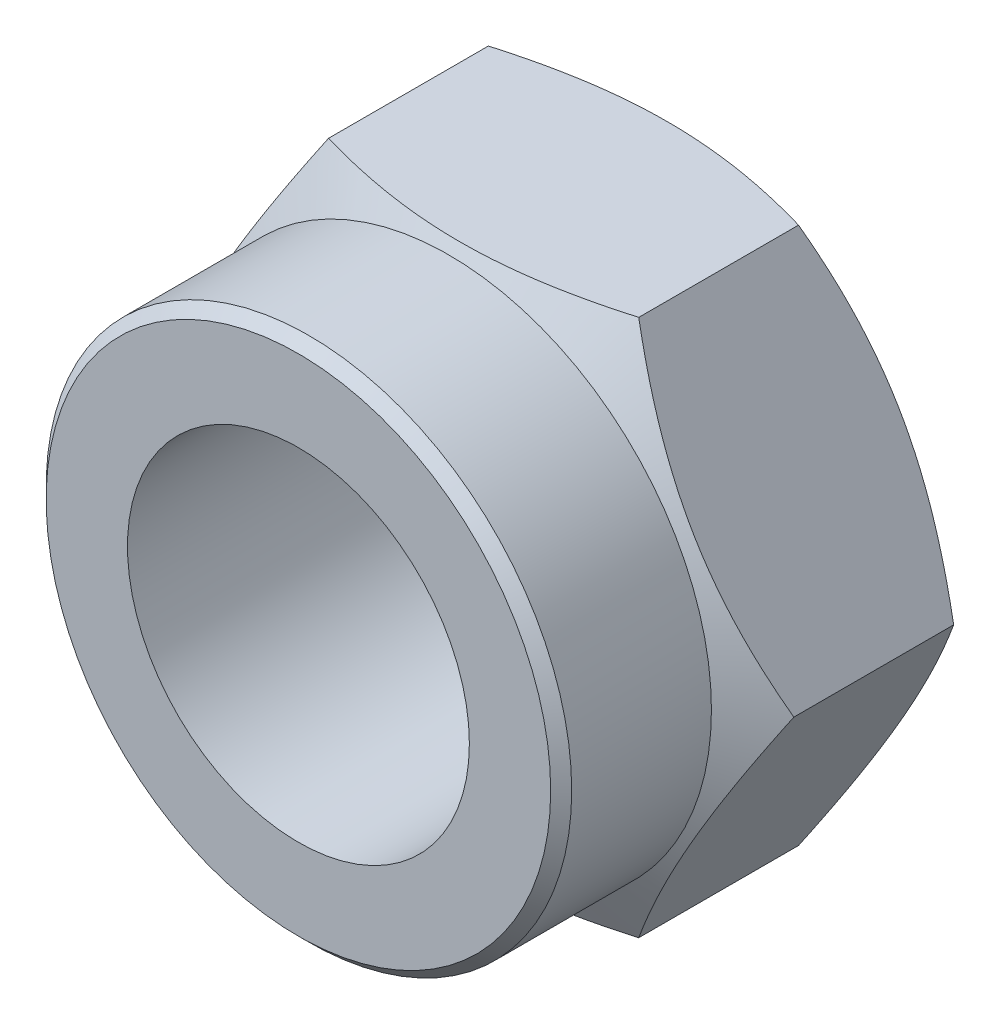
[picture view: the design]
ISO-10303-21;
HEADER;
FILE_DESCRIPTION(('STEP AP214'),'2;1');
FILE_NAME('part.step','',(''),(''),'','','');
FILE_SCHEMA(('AUTOMOTIVE_DESIGN { 1 0 10303 214 1 1 1 1 }'));
ENDSEC;
DATA;
#1=APPLICATION_CONTEXT('core data for automotive mechanical design processes');
#2=APPLICATION_PROTOCOL_DEFINITION('international standard','automotive_design',2000,#1);
#3=PRODUCT_CONTEXT('',#1,'mechanical');
#4=PRODUCT('Part','Part','',(#3));
#5=PRODUCT_RELATED_PRODUCT_CATEGORY('part','',(#4));
#6=PRODUCT_DEFINITION_FORMATION('','',#4);
#7=PRODUCT_DEFINITION_CONTEXT('part definition',#1,'design');
#8=PRODUCT_DEFINITION('design','',#6,#7);
#9=PRODUCT_DEFINITION_SHAPE('','',#8);
#10=(LENGTH_UNIT() NAMED_UNIT(*) SI_UNIT(.MILLI.,.METRE.));
#11=(NAMED_UNIT(*) PLANE_ANGLE_UNIT() SI_UNIT($,.RADIAN.));
#12=(NAMED_UNIT(*) SI_UNIT($,.STERADIAN.) SOLID_ANGLE_UNIT());
#13=UNCERTAINTY_MEASURE_WITH_UNIT(LENGTH_MEASURE(1.E-05),#10,'distance_accuracy_value','');
#14=(GEOMETRIC_REPRESENTATION_CONTEXT(3) GLOBAL_UNCERTAINTY_ASSIGNED_CONTEXT((#13)) GLOBAL_UNIT_ASSIGNED_CONTEXT((#10,
#11,#12)) REPRESENTATION_CONTEXT('',''));
#15=CARTESIAN_POINT('',(0.,0.,0.));
#16=DIRECTION('',(0.,0.,1.));
#17=DIRECTION('',(1.,0.,0.));
#18=AXIS2_PLACEMENT_3D('',#15,#16,#17);
#19=CARTESIAN_POINT('',(15.8771324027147,-27.5,-23.52));
#20=DIRECTION('',(0.,0.,1.));
#21=DIRECTION('',(1.,0.,0.));
#22=AXIS2_PLACEMENT_3D('',#19,#20,#21);
#23=PLANE('',#22);
#24=CARTESIAN_POINT('',(0.,0.,-23.52));
#25=DIRECTION('',(0.,0.,-1.));
#26=DIRECTION('',(-1.,0.,0.));
#27=AXIS2_PLACEMENT_3D('',#24,#25,#26);
#28=CIRCLE('',#27,25.555);
#29=CARTESIAN_POINT('',(-25.555,0.,-23.52));
#30=VERTEX_POINT('',#29);
#31=EDGE_CURVE('E268',#30,#30,#28,.T.);
#32=ORIENTED_EDGE('',*,*,#31,.T.);
#33=EDGE_LOOP('',(#32));
#34=FACE_BOUND('',#33,.T.);
#35=CARTESIAN_POINT('',(0.,0.,-23.52));
#36=DIRECTION('',(0.,0.,-1.));
#37=DIRECTION('',(-1.,0.,0.));
#38=AXIS2_PLACEMENT_3D('',#35,#36,#37);
#39=CIRCLE('',#38,19.45);
#40=CARTESIAN_POINT('',(-19.45,0.,-23.52));
#41=VERTEX_POINT('',#40);
#42=EDGE_CURVE('E281',#41,#41,#39,.T.);
#43=ORIENTED_EDGE('',*,*,#42,.F.);
#44=EDGE_LOOP('',(#43));
#45=FACE_BOUND('',#44,.T.);
#46=ADVANCED_FACE('F43',(#34,#45),#23,.F.);
#47=CARTESIAN_POINT('',(0.,0.,-23.52));
#48=DIRECTION('',(0.,0.,1.));
#49=DIRECTION('',(1.,0.,0.));
#50=AXIS2_PLACEMENT_3D('',#47,#48,#49);
#51=CYLINDRICAL_SURFACE('',#50,17.5);
#52=CARTESIAN_POINT('',(0.,0.,15.38));
#53=DIRECTION('',(0.,0.,1.));
#54=DIRECTION('',(1.,0.,0.));
#55=AXIS2_PLACEMENT_3D('',#52,#53,#54);
#56=CIRCLE('',#55,17.5);
#57=CARTESIAN_POINT('',(17.5,0.,15.38));
#58=VERTEX_POINT('',#57);
#59=EDGE_CURVE('E280',#58,#58,#56,.T.);
#60=ORIENTED_EDGE('',*,*,#59,.T.);
#61=EDGE_LOOP('',(#60));
#62=FACE_BOUND('',#61,.T.);
#63=CARTESIAN_POINT('',(0.,0.,-21.57));
#64=DIRECTION('',(0.,0.,-1.));
#65=DIRECTION('',(-1.,0.,0.));
#66=AXIS2_PLACEMENT_3D('',#63,#64,#65);
#67=CIRCLE('',#66,17.5);
#68=CARTESIAN_POINT('',(-17.5,0.,-21.57));
#69=VERTEX_POINT('',#68);
#70=EDGE_CURVE('E289',#69,#69,#67,.T.);
#71=ORIENTED_EDGE('',*,*,#70,.T.);
#72=EDGE_LOOP('',(#71));
#73=FACE_BOUND('',#72,.T.);
#74=ADVANCED_FACE('F146',(#62,#73),#51,.F.);
#75=CARTESIAN_POINT('',(-15.8771324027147,-27.5,-23.52));
#76=DIRECTION('',(0.,-1.,0.));
#77=DIRECTION('',(1.,0.,0.));
#78=AXIS2_PLACEMENT_3D('',#75,#76,#77);
#79=PLANE('',#78);
#80=DIRECTION('',(0.,0.,1.));
#81=VECTOR('',#80,1.);
#82=CARTESIAN_POINT('',(15.8771324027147,-27.5,-23.52));
#83=LINE('',#82,#81);
#84=CARTESIAN_POINT('',(15.8771324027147,-27.5,-19.9408527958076));
#85=VERTEX_POINT('',#84);
#86=CARTESIAN_POINT('',(15.8771324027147,-27.5,-3.57914720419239));
#87=VERTEX_POINT('',#86);
#88=EDGE_CURVE('E126',#85,#87,#83,.T.);
#89=ORIENTED_EDGE('',*,*,#88,.T.);
#90=CARTESIAN_POINT('',(-41.9529404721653,-27.5,-14.2072780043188));
#91=CARTESIAN_POINT('',(-41.3498619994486,-27.5,-13.9160849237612));
#92=CARTESIAN_POINT('',(-40.7460496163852,-27.5,-13.6264069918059));
#93=CARTESIAN_POINT('',(-39.5368030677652,-27.5,-13.0504395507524));
#94=CARTESIAN_POINT('',(-38.9313688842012,-27.5,-12.7641500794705));
#95=CARTESIAN_POINT('',(-37.7186338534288,-27.5,-12.1952752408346));
#96=CARTESIAN_POINT('',(-37.1113327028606,-27.5,-11.9126905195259));
#97=CARTESIAN_POINT('',(-35.8948027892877,-27.5,-11.351707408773));
#98=CARTESIAN_POINT('',(-35.2855740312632,-27.5,-11.0733090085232));
#99=CARTESIAN_POINT('',(-33.4476550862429,-27.5,-10.2418974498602));
#100=CARTESIAN_POINT('',(-32.2157452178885,-27.5,-9.69597054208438));
#101=CARTESIAN_POINT('',(-29.7417380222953,-27.5,-8.62775844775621));
#102=CARTESIAN_POINT('',(-28.4996412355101,-27.5,-8.1054720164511));
#103=CARTESIAN_POINT('',(-26.6200225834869,-27.5,-7.34162955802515));
#104=CARTESIAN_POINT('',(-25.9870438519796,-27.5,-7.08888221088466));
#105=CARTESIAN_POINT('',(-24.7176705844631,-27.5,-6.59212719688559));
#106=CARTESIAN_POINT('',(-24.0812761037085,-27.5,-6.34811938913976));
#107=CARTESIAN_POINT('',(-22.8046783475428,-27.5,-5.8699696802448));
#108=CARTESIAN_POINT('',(-22.1644745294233,-27.5,-5.63582922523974));
#109=CARTESIAN_POINT('',(-20.8800742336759,-27.5,-5.17879930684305));
#110=CARTESIAN_POINT('',(-20.2358778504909,-27.5,-4.95590957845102));
#111=CARTESIAN_POINT('',(-18.944590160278,-27.5,-4.52336181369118));
#112=CARTESIAN_POINT('',(-18.2975081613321,-27.5,-4.3136761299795));
#113=CARTESIAN_POINT('',(-16.9988609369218,-27.5,-3.90872451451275));
#114=CARTESIAN_POINT('',(-16.3472956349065,-27.5,-3.71345882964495));
#115=CARTESIAN_POINT('',(-14.3858917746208,-27.5,-3.1521805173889));
#116=CARTESIAN_POINT('',(-13.0688434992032,-27.5,-2.81051560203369));
#117=CARTESIAN_POINT('',(-11.0791469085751,-27.5,-2.35941057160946));
#118=CARTESIAN_POINT('',(-10.4133851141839,-27.5,-2.2192457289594));
#119=CARTESIAN_POINT('',(-9.07745639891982,-27.5,-1.96161324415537));
#120=CARTESIAN_POINT('',(-8.407289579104,-27.5,-1.84414508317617));
#121=CARTESIAN_POINT('',(-7.06301937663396,-27.5,-1.63399737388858));
#122=CARTESIAN_POINT('',(-6.38891574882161,-27.5,-1.54131938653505));
#123=CARTESIAN_POINT('',(-5.03755485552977,-27.5,-1.38261853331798));
#124=CARTESIAN_POINT('',(-4.3602975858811,-27.5,-1.31659570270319));
#125=CARTESIAN_POINT('',(-3.00782609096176,-27.5,-1.21297427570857));
#126=CARTESIAN_POINT('',(-2.33262527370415,-27.5,-1.1752018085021));
#127=CARTESIAN_POINT('',(-0.981233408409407,-27.5,-1.12827728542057));
#128=CARTESIAN_POINT('',(-0.305042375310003,-27.5,-1.11912480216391));
#129=CARTESIAN_POINT('',(1.04693403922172,-27.5,-1.12965648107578));
#130=CARTESIAN_POINT('',(1.72271948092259,-27.5,-1.14933283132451));
#131=CARTESIAN_POINT('',(3.07287323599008,-27.5,-1.2170378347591));
#132=CARTESIAN_POINT('',(3.7472414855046,-27.5,-1.26506773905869));
#133=CARTESIAN_POINT('',(5.38622566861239,-27.5,-1.41526016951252));
#134=CARTESIAN_POINT('',(6.34953811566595,-27.5,-1.53188000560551));
#135=CARTESIAN_POINT('',(8.26856130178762,-27.5,-1.81645090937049));
#136=CARTESIAN_POINT('',(9.22427087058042,-27.5,-1.98440972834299));
#137=CARTESIAN_POINT('',(11.12860836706,-27.5,-2.36594258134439));
#138=CARTESIAN_POINT('',(12.0772164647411,-27.5,-2.57961465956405));
#139=CARTESIAN_POINT('',(13.9646711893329,-27.5,-3.04594688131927));
#140=CARTESIAN_POINT('',(14.9035181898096,-27.5,-3.29860552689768));
#141=CARTESIAN_POINT('',(16.7933423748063,-27.5,-3.84312729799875));
#142=CARTESIAN_POINT('',(17.7440949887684,-27.5,-4.13576455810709));
#143=CARTESIAN_POINT('',(19.6362862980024,-27.5,-4.74984233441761));
#144=CARTESIAN_POINT('',(20.5777241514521,-27.5,-5.07128542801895));
#145=CARTESIAN_POINT('',(22.4467523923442,-27.5,-5.73620174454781));
#146=CARTESIAN_POINT('',(23.3743910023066,-27.5,-6.07953993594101));
#147=CARTESIAN_POINT('',(24.7600183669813,-27.5,-6.60924818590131));
#148=CARTESIAN_POINT('',(25.2208494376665,-27.5,-6.78823807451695));
#149=CARTESIAN_POINT('',(26.1407238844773,-27.5,-7.15071875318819));
#150=CARTESIAN_POINT('',(26.5997673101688,-27.5,-7.33420941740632));
#151=CARTESIAN_POINT('',(27.0579825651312,-27.5,-7.51974796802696));
#152=B_SPLINE_CURVE_WITH_KNOTS('',3,(#90,#91,#92,#93,#94,#95,#96,#97,#98,#99,#100,#101,#102,
#103,#104,#105,#106,#107,#108,#109,#110,#111,#112,#113,#114,#115,#116,#117,#118,#119,#120,#121,
#122,#123,#124,#125,#126,#127,#128,#129,#130,#131,#132,#133,#134,#135,#136,#137,#138,#139,#140,
#141,#142,#143,#144,#145,#146,#147,#148,#149,#150,#151),.UNSPECIFIED.,.F.,.F.,(4,2,2,2,2,2,2,2,
2,2,2,2,2,2,2,2,2,2,2,2,2,2,2,2,2,2,2,2,2,2,4),(0.,2.00909855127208,4.01821950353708,
6.02768627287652,8.03714785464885,12.0793239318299,16.121286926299,18.1659567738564,
20.2105936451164,22.2555291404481,24.3004164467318,26.3408689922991,28.3813564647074,
32.4607424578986,34.5015007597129,36.5422124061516,38.5830525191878,40.6238953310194,
42.6520717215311,44.6802178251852,46.7078144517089,48.7355005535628,51.6449146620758,
54.5547682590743,57.4709265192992,60.3869727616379,63.3707330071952,66.3547604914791,
69.3218933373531,70.8049872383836,72.2880397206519),.UNSPECIFIED.);
#153=CARTESIAN_POINT('',(-15.8771324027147,-27.5,-3.5791472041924));
#154=VERTEX_POINT('',#153);
#155=EDGE_CURVE('E59',#87,#154,#152,.F.);
#156=ORIENTED_EDGE('',*,*,#155,.T.);
#157=DIRECTION('',(0.,0.,1.));
#158=VECTOR('',#157,1.);
#159=CARTESIAN_POINT('',(-15.8771324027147,-27.5,-23.52));
#160=LINE('',#159,#158);
#161=CARTESIAN_POINT('',(-15.8771324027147,-27.5,-19.9408527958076));
#162=VERTEX_POINT('',#161);
#163=EDGE_CURVE('E115',#162,#154,#160,.T.);
#164=ORIENTED_EDGE('',*,*,#163,.F.);
#165=CARTESIAN_POINT('',(-41.9529404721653,-27.5,-9.31272199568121));
#166=CARTESIAN_POINT('',(-41.3498619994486,-27.5,-9.60391507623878));
#167=CARTESIAN_POINT('',(-40.7460496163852,-27.5,-9.89359300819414));
#168=CARTESIAN_POINT('',(-39.5368030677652,-27.5,-10.4695604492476));
#169=CARTESIAN_POINT('',(-38.9313688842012,-27.5,-10.7558499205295));
#170=CARTESIAN_POINT('',(-37.7186338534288,-27.5,-11.3247247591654));
#171=CARTESIAN_POINT('',(-37.1113327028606,-27.5,-11.607309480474));
#172=CARTESIAN_POINT('',(-35.8948027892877,-27.5,-12.168292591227));
#173=CARTESIAN_POINT('',(-35.2855740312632,-27.5,-12.4466909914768));
#174=CARTESIAN_POINT('',(-33.4476550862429,-27.5,-13.2781025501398));
#175=CARTESIAN_POINT('',(-32.2157452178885,-27.5,-13.8240294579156));
#176=CARTESIAN_POINT('',(-29.7417380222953,-27.5,-14.8922415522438));
#177=CARTESIAN_POINT('',(-28.4996412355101,-27.5,-15.4145279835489));
#178=CARTESIAN_POINT('',(-26.6200225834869,-27.5,-16.1783704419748));
#179=CARTESIAN_POINT('',(-25.9870438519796,-27.5,-16.4311177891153));
#180=CARTESIAN_POINT('',(-24.7176705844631,-27.5,-16.9278728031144));
#181=CARTESIAN_POINT('',(-24.0812761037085,-27.5,-17.1718806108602));
#182=CARTESIAN_POINT('',(-22.8046783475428,-27.5,-17.6500303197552));
#183=CARTESIAN_POINT('',(-22.1644745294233,-27.5,-17.8841707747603));
#184=CARTESIAN_POINT('',(-20.8800742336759,-27.5,-18.341200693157));
#185=CARTESIAN_POINT('',(-20.2358778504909,-27.5,-18.564090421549));
#186=CARTESIAN_POINT('',(-18.944590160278,-27.5,-18.9966381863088));
#187=CARTESIAN_POINT('',(-18.2975081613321,-27.5,-19.2063238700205));
#188=CARTESIAN_POINT('',(-16.9988609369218,-27.5,-19.6112754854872));
#189=CARTESIAN_POINT('',(-16.3472956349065,-27.5,-19.806541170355));
#190=CARTESIAN_POINT('',(-14.3858917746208,-27.5,-20.3678194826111));
#191=CARTESIAN_POINT('',(-13.0688434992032,-27.5,-20.7094843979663));
#192=CARTESIAN_POINT('',(-11.0791469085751,-27.5,-21.1605894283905));
#193=CARTESIAN_POINT('',(-10.4133851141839,-27.5,-21.3007542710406));
#194=CARTESIAN_POINT('',(-9.07745639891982,-27.5,-21.5583867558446));
#195=CARTESIAN_POINT('',(-8.407289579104,-27.5,-21.6758549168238));
#196=CARTESIAN_POINT('',(-7.06301937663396,-27.5,-21.8860026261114));
#197=CARTESIAN_POINT('',(-6.38891574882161,-27.5,-21.9786806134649));
#198=CARTESIAN_POINT('',(-5.03755485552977,-27.5,-22.137381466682));
#199=CARTESIAN_POINT('',(-4.3602975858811,-27.5,-22.2034042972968));
#200=CARTESIAN_POINT('',(-3.00782609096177,-27.5,-22.3070257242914));
#201=CARTESIAN_POINT('',(-2.33262527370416,-27.5,-22.3447981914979));
#202=CARTESIAN_POINT('',(-0.981233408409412,-27.5,-22.3917227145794));
#203=CARTESIAN_POINT('',(-0.305042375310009,-27.5,-22.4008751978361));
#204=CARTESIAN_POINT('',(1.04693403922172,-27.5,-22.3903435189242));
#205=CARTESIAN_POINT('',(1.72271948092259,-27.5,-22.3706671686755));
#206=CARTESIAN_POINT('',(3.07287323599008,-27.5,-22.3029621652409));
#207=CARTESIAN_POINT('',(3.7472414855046,-27.5,-22.2549322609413));
#208=CARTESIAN_POINT('',(5.38622566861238,-27.5,-22.1047398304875));
#209=CARTESIAN_POINT('',(6.34953811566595,-27.5,-21.9881199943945));
#210=CARTESIAN_POINT('',(8.26856130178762,-27.5,-21.7035490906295));
#211=CARTESIAN_POINT('',(9.22427087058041,-27.5,-21.535590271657));
#212=CARTESIAN_POINT('',(11.12860836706,-27.5,-21.1540574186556));
#213=CARTESIAN_POINT('',(12.0772164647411,-27.5,-20.9403853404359));
#214=CARTESIAN_POINT('',(13.9646711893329,-27.5,-20.4740531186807));
#215=CARTESIAN_POINT('',(14.9035181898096,-27.5,-20.2213944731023));
#216=CARTESIAN_POINT('',(16.7933423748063,-27.5,-19.6768727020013));
#217=CARTESIAN_POINT('',(17.7440949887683,-27.5,-19.3842354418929));
#218=CARTESIAN_POINT('',(19.6362862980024,-27.5,-18.7701576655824));
#219=CARTESIAN_POINT('',(20.577724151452,-27.5,-18.448714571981));
#220=CARTESIAN_POINT('',(22.4467523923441,-27.5,-17.7837982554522));
#221=CARTESIAN_POINT('',(23.3743910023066,-27.5,-17.440460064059));
#222=CARTESIAN_POINT('',(24.7600183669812,-27.5,-16.9107518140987));
#223=CARTESIAN_POINT('',(25.2208494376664,-27.5,-16.7317619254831));
#224=CARTESIAN_POINT('',(26.1407238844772,-27.5,-16.3692812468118));
#225=CARTESIAN_POINT('',(26.5997673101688,-27.5,-16.1857905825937));
#226=CARTESIAN_POINT('',(27.0579825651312,-27.5,-16.000252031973));
#227=B_SPLINE_CURVE_WITH_KNOTS('',3,(#165,#166,#167,#168,#169,#170,#171,#172,#173,#174,#175,
#176,#177,#178,#179,#180,#181,#182,#183,#184,#185,#186,#187,#188,#189,#190,#191,#192,#193,#194,
#195,#196,#197,#198,#199,#200,#201,#202,#203,#204,#205,#206,#207,#208,#209,#210,#211,#212,#213,
#214,#215,#216,#217,#218,#219,#220,#221,#222,#223,#224,#225,#226),.UNSPECIFIED.,.F.,.F.,(4,2,2,
2,2,2,2,2,2,2,2,2,2,2,2,2,2,2,2,2,2,2,2,2,2,2,2,2,2,2,4),(0.,2.00909855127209,4.01821950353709,
6.02768627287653,8.03714785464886,12.0793239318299,16.1212869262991,18.1659567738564,
20.2105936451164,22.2555291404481,24.3004164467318,26.3408689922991,28.3813564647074,
32.4607424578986,34.5015007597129,36.5422124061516,38.5830525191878,40.6238953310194,
42.6520717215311,44.6802178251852,46.7078144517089,48.7355005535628,51.6449146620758,
54.5547682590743,57.4709265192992,60.3869727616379,63.3707330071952,66.354760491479,
69.321893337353,70.8049872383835,72.2880397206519),.UNSPECIFIED.);
#228=EDGE_CURVE('E134',#162,#85,#227,.T.);
#229=ORIENTED_EDGE('',*,*,#228,.T.);
#230=EDGE_LOOP('',(#89,#156,#164,#229));
#231=FACE_BOUND('',#230,.T.);
#232=ADVANCED_FACE('F156',(#231),#79,.T.);
#233=CARTESIAN_POINT('',(-31.7542648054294,0.,-23.52));
#234=DIRECTION('',(-0.866025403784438,-0.5,0.));
#235=DIRECTION('',(0.5,-0.866025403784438,0.));
#236=AXIS2_PLACEMENT_3D('',#233,#234,#235);
#237=PLANE('',#236);
#238=ORIENTED_EDGE('',*,*,#163,.T.);
#239=CARTESIAN_POINT('',(-15.8770169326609,-27.5002,-3.57921387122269));
#240=CARTESIAN_POINT('',(-16.2259892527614,-26.8957622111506,-3.37774962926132));
#241=CARTESIAN_POINT('',(-16.5763227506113,-26.2889667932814,-3.18542761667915));
#242=CARTESIAN_POINT('',(-17.2797989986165,-25.0705101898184,-2.82160924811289));
#243=CARTESIAN_POINT('',(-17.6329426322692,-24.4588474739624,-2.65011974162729));
#244=CARTESIAN_POINT('',(-18.3427291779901,-23.229461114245,-2.33026818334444));
#245=CARTESIAN_POINT('',(-18.6993783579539,-22.6117266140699,-2.18196136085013));
#246=CARTESIAN_POINT('',(-19.4151397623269,-21.371991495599,-1.91167004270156));
#247=CARTESIAN_POINT('',(-19.7742517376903,-20.7499913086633,-1.78968292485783));
#248=CARTESIAN_POINT('',(-20.4857595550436,-19.5176236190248,-1.57720918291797));
#249=CARTESIAN_POINT('',(-20.8381026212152,-18.907347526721,-1.48601990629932));
#250=CARTESIAN_POINT('',(-21.5444032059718,-17.683999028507,-1.33311646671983));
#251=CARTESIAN_POINT('',(-21.8983607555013,-17.0709265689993,-1.27140287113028));
#252=CARTESIAN_POINT('',(-22.6068704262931,-15.8437518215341,-1.17900903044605));
#253=CARTESIAN_POINT('',(-22.9614213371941,-15.2296516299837,-1.14829190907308));
#254=CARTESIAN_POINT('',(-23.6708503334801,-14.0008845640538,-1.11855157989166));
#255=CARTESIAN_POINT('',(-24.025728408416,-13.3862177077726,-1.11952739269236));
#256=CARTESIAN_POINT('',(-24.6891773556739,-12.2370904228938,-1.15095918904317));
#257=CARTESIAN_POINT('',(-24.9977954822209,-11.7025481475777,-1.17758234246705));
#258=CARTESIAN_POINT('',(-25.6142949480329,-10.6347397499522,-1.25429236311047));
#259=CARTESIAN_POINT('',(-25.9221762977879,-10.1014736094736,-1.30437889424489));
#260=CARTESIAN_POINT('',(-26.5370884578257,-9.03641450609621,-1.42714762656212));
#261=CARTESIAN_POINT('',(-26.8441182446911,-8.50462331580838,-1.49985026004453));
#262=CARTESIAN_POINT('',(-27.4567077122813,-7.44358723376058,-1.66656449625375));
#263=CARTESIAN_POINT('',(-27.7622673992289,-6.9143423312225,-1.76057600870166));
#264=CARTESIAN_POINT('',(-28.6898814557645,-5.30766765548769,-2.07698651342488));
#265=CARTESIAN_POINT('',(-29.3093003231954,-4.23480270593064,-2.33095223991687));
#266=CARTESIAN_POINT('',(-30.2315881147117,-2.63735339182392,-2.76331683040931));
#267=CARTESIAN_POINT('',(-30.5376130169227,-2.10730271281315,-2.91585211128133));
#268=CARTESIAN_POINT('',(-31.1475461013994,-1.05086762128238,-3.23636496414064));
#269=CARTESIAN_POINT('',(-31.4514548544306,-0.524482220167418,-3.40433818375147));
#270=CARTESIAN_POINT('',(-31.7543802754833,0.000200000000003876,-3.5792138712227));
#271=B_SPLINE_CURVE_WITH_KNOTS('',3,(#239,#240,#241,#242,#243,#244,#245,#246,#247,#248,#249,
#250,#251,#252,#253,#254,#255,#256,#257,#258,#259,#260,#261,#262,#263,#264,#265,#266,#267,#268,
#269,#270),.UNSPECIFIED.,.F.,.F.,(4,2,2,2,2,2,2,2,2,2,2,2,2,2,2,4),(0.,2.17937596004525,
4.35946654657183,6.54467421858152,8.72966408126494,10.8607692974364,12.9919155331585,
15.120523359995,17.2490654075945,19.1020483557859,20.9550047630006,22.8096400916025,
24.6642675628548,28.4552152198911,30.3473870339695,32.2390270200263),.UNSPECIFIED.);
#272=CARTESIAN_POINT('',(-31.7542648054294,0.,-3.5791472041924));
#273=VERTEX_POINT('',#272);
#274=EDGE_CURVE('E97',#154,#273,#271,.T.);
#275=ORIENTED_EDGE('',*,*,#274,.T.);
#276=DIRECTION('',(0.,0.,1.));
#277=VECTOR('',#276,1.);
#278=CARTESIAN_POINT('',(-31.7542648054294,0.,-23.52));
#279=LINE('',#278,#277);
#280=CARTESIAN_POINT('',(-31.7542648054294,0.,-19.9408527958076));
#281=VERTEX_POINT('',#280);
#282=EDGE_CURVE('E109',#281,#273,#279,.T.);
#283=ORIENTED_EDGE('',*,*,#282,.F.);
#284=CARTESIAN_POINT('',(-31.7543802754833,0.00020000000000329,-19.9407861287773));
#285=CARTESIAN_POINT('',(-31.4054079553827,-0.604237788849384,-20.1422503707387));
#286=CARTESIAN_POINT('',(-31.0550744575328,-1.21103320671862,-20.3345723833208));
#287=CARTESIAN_POINT('',(-30.3515982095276,-2.42948981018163,-20.6983907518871));
#288=CARTESIAN_POINT('',(-29.9984545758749,-3.04115252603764,-20.8698802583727));
#289=CARTESIAN_POINT('',(-29.288668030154,-4.27053888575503,-21.1897318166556));
#290=CARTESIAN_POINT('',(-28.9320188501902,-4.88827338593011,-21.3380386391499));
#291=CARTESIAN_POINT('',(-28.2162574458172,-6.128008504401,-21.6083299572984));
#292=CARTESIAN_POINT('',(-27.8571454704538,-6.75000869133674,-21.7303170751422));
#293=CARTESIAN_POINT('',(-27.1456376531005,-7.98237638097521,-21.942790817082));
#294=CARTESIAN_POINT('',(-26.7932945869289,-8.59265247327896,-22.0339800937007));
#295=CARTESIAN_POINT('',(-26.0869940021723,-9.81600097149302,-22.1868835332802));
#296=CARTESIAN_POINT('',(-25.7330364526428,-10.4290734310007,-22.2485971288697));
#297=CARTESIAN_POINT('',(-25.024526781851,-11.6562481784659,-22.340990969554));
#298=CARTESIAN_POINT('',(-24.66997587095,-12.2703483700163,-22.3717080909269));
#299=CARTESIAN_POINT('',(-23.960546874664,-13.4991154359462,-22.4014484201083));
#300=CARTESIAN_POINT('',(-23.6056687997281,-14.1137822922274,-22.4004726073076));
#301=CARTESIAN_POINT('',(-22.9422198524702,-15.2629095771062,-22.3690408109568));
#302=CARTESIAN_POINT('',(-22.6336017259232,-15.7974518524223,-22.342417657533));
#303=CARTESIAN_POINT('',(-22.0171022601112,-16.8652602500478,-22.2657076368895));
#304=CARTESIAN_POINT('',(-21.7092209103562,-17.3985263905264,-22.2156211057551));
#305=CARTESIAN_POINT('',(-21.0943087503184,-18.4635854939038,-22.0928523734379));
#306=CARTESIAN_POINT('',(-20.787278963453,-18.9953766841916,-22.0201497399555));
#307=CARTESIAN_POINT('',(-20.1746894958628,-20.0564127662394,-21.8534355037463));
#308=CARTESIAN_POINT('',(-19.8691298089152,-20.5856576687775,-21.7594239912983));
#309=CARTESIAN_POINT('',(-18.9415157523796,-22.1923323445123,-21.4430134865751));
#310=CARTESIAN_POINT('',(-18.3220968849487,-23.2651972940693,-21.1890477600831));
#311=CARTESIAN_POINT('',(-17.3998090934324,-24.8626466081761,-20.7566831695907));
#312=CARTESIAN_POINT('',(-17.0937841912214,-25.3926972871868,-20.6041478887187));
#313=CARTESIAN_POINT('',(-16.4838511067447,-26.4491323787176,-20.2836350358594));
#314=CARTESIAN_POINT('',(-16.1799423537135,-26.9755177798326,-20.1156618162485));
#315=CARTESIAN_POINT('',(-15.8770169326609,-27.5002,-19.9407861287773));
#316=B_SPLINE_CURVE_WITH_KNOTS('',3,(#284,#285,#286,#287,#288,#289,#290,#291,#292,#293,#294,
#295,#296,#297,#298,#299,#300,#301,#302,#303,#304,#305,#306,#307,#308,#309,#310,#311,#312,#313,
#314,#315),.UNSPECIFIED.,.F.,.F.,(4,2,2,2,2,2,2,2,2,2,2,2,2,2,2,4),(0.,2.17937596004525,
4.35946654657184,6.54467421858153,8.72966408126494,10.8607692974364,12.9919155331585,
15.120523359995,17.2490654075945,19.1020483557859,20.9550047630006,22.8096400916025,
24.6642675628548,28.4552152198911,30.3473870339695,32.2390270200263),.UNSPECIFIED.);
#317=EDGE_CURVE('E171',#281,#162,#316,.T.);
#318=ORIENTED_EDGE('',*,*,#317,.T.);
#319=EDGE_LOOP('',(#238,#275,#283,#318));
#320=FACE_BOUND('',#319,.T.);
#321=ADVANCED_FACE('F108',(#320),#237,.T.);
#322=CARTESIAN_POINT('',(-15.8771324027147,27.5,-23.52));
#323=DIRECTION('',(-0.866025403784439,0.5,0.));
#324=DIRECTION('',(-0.5,-0.866025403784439,0.));
#325=AXIS2_PLACEMENT_3D('',#322,#323,#324);
#326=PLANE('',#325);
#327=ORIENTED_EDGE('',*,*,#282,.T.);
#328=CARTESIAN_POINT('',(-31.7543802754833,-0.000199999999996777,-3.5792138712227));
#329=CARTESIAN_POINT('',(-31.4054079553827,0.60423778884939,-3.37774962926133));
#330=CARTESIAN_POINT('',(-31.0550744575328,1.21103320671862,-3.18542761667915));
#331=CARTESIAN_POINT('',(-30.3515982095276,2.42948981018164,-2.8216092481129));
#332=CARTESIAN_POINT('',(-29.9984545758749,3.04115252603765,-2.6501197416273));
#333=CARTESIAN_POINT('',(-29.288668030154,4.27053888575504,-2.33026818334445));
#334=CARTESIAN_POINT('',(-28.9320188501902,4.88827338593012,-2.18196136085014));
#335=CARTESIAN_POINT('',(-28.2162574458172,6.12800850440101,-1.91167004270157));
#336=CARTESIAN_POINT('',(-27.8571454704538,6.75000869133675,-1.78968292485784));
#337=CARTESIAN_POINT('',(-27.1456376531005,7.98237638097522,-1.57720918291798));
#338=CARTESIAN_POINT('',(-26.7932945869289,8.59265247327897,-1.48601990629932));
#339=CARTESIAN_POINT('',(-26.0869940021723,9.81600097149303,-1.33311646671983));
#340=CARTESIAN_POINT('',(-25.7330364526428,10.4290734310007,-1.27140287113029));
#341=CARTESIAN_POINT('',(-25.024526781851,11.6562481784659,-1.17900903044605));
#342=CARTESIAN_POINT('',(-24.66997587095,12.2703483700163,-1.14829190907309));
#343=CARTESIAN_POINT('',(-23.960546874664,13.4991154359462,-1.11855157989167));
#344=CARTESIAN_POINT('',(-23.6056687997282,14.1137822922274,-1.11952739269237));
#345=CARTESIAN_POINT('',(-22.9422198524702,15.2629095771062,-1.15095918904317));
#346=CARTESIAN_POINT('',(-22.6336017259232,15.7974518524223,-1.17758234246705));
#347=CARTESIAN_POINT('',(-22.0171022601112,16.8652602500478,-1.25429236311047));
#348=CARTESIAN_POINT('',(-21.7092209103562,17.3985263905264,-1.3043788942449));
#349=CARTESIAN_POINT('',(-21.0943087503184,18.4635854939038,-1.42714762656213));
#350=CARTESIAN_POINT('',(-20.787278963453,18.9953766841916,-1.49985026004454));
#351=CARTESIAN_POINT('',(-20.1746894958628,20.0564127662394,-1.66656449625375));
#352=CARTESIAN_POINT('',(-19.8691298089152,20.5856576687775,-1.76057600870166));
#353=CARTESIAN_POINT('',(-18.9415157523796,22.1923323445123,-2.07698651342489));
#354=CARTESIAN_POINT('',(-18.3220968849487,23.2651972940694,-2.33095223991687));
#355=CARTESIAN_POINT('',(-17.3998090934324,24.8626466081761,-2.76331683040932));
#356=CARTESIAN_POINT('',(-17.0937841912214,25.3926972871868,-2.91585211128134));
#357=CARTESIAN_POINT('',(-16.4838511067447,26.4491323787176,-3.23636496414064));
#358=CARTESIAN_POINT('',(-16.1799423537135,26.9755177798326,-3.40433818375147));
#359=CARTESIAN_POINT('',(-15.8770169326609,27.5002,-3.5792138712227));
#360=B_SPLINE_CURVE_WITH_KNOTS('',3,(#328,#329,#330,#331,#332,#333,#334,#335,#336,#337,#338,
#339,#340,#341,#342,#343,#344,#345,#346,#347,#348,#349,#350,#351,#352,#353,#354,#355,#356,#357,
#358,#359),.UNSPECIFIED.,.F.,.F.,(4,2,2,2,2,2,2,2,2,2,2,2,2,2,2,4),(0.,2.17937596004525,
4.35946654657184,6.54467421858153,8.72966408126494,10.8607692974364,12.9919155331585,
15.120523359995,17.2490654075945,19.1020483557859,20.9550047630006,22.8096400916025,
24.6642675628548,28.4552152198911,30.3473870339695,32.2390270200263),.UNSPECIFIED.);
#361=CARTESIAN_POINT('',(-15.8771324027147,27.5,-3.5791472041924));
#362=VERTEX_POINT('',#361);
#363=EDGE_CURVE('E93',#273,#362,#360,.T.);
#364=ORIENTED_EDGE('',*,*,#363,.T.);
#365=DIRECTION('',(0.,0.,1.));
#366=VECTOR('',#365,1.);
#367=CARTESIAN_POINT('',(-15.8771324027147,27.5,-23.52));
#368=LINE('',#367,#366);
#369=CARTESIAN_POINT('',(-15.8771324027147,27.5,-19.9408527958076));
#370=VERTEX_POINT('',#369);
#371=EDGE_CURVE('E120',#370,#362,#368,.T.);
#372=ORIENTED_EDGE('',*,*,#371,.F.);
#373=CARTESIAN_POINT('',(-15.8770169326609,27.5002,-19.9407861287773));
#374=CARTESIAN_POINT('',(-16.2259892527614,26.8957622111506,-20.1422503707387));
#375=CARTESIAN_POINT('',(-16.5763227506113,26.2889667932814,-20.3345723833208));
#376=CARTESIAN_POINT('',(-17.2797989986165,25.0705101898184,-20.6983907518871));
#377=CARTESIAN_POINT('',(-17.6329426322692,24.4588474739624,-20.8698802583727));
#378=CARTESIAN_POINT('',(-18.3427291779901,23.229461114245,-21.1897318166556));
#379=CARTESIAN_POINT('',(-18.6993783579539,22.6117266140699,-21.3380386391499));
#380=CARTESIAN_POINT('',(-19.4151397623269,21.371991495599,-21.6083299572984));
#381=CARTESIAN_POINT('',(-19.7742517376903,20.7499913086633,-21.7303170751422));
#382=CARTESIAN_POINT('',(-20.4857595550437,19.5176236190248,-21.942790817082));
#383=CARTESIAN_POINT('',(-20.8381026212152,18.907347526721,-22.0339800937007));
#384=CARTESIAN_POINT('',(-21.5444032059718,17.683999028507,-22.1868835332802));
#385=CARTESIAN_POINT('',(-21.8983607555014,17.0709265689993,-22.2485971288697));
#386=CARTESIAN_POINT('',(-22.6068704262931,15.8437518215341,-22.3409909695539));
#387=CARTESIAN_POINT('',(-22.9614213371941,15.2296516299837,-22.3717080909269));
#388=CARTESIAN_POINT('',(-23.6708503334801,14.0008845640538,-22.4014484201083));
#389=CARTESIAN_POINT('',(-24.025728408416,13.3862177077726,-22.4004726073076));
#390=CARTESIAN_POINT('',(-24.6891773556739,12.2370904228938,-22.3690408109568));
#391=CARTESIAN_POINT('',(-24.9977954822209,11.7025481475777,-22.3424176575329));
#392=CARTESIAN_POINT('',(-25.6142949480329,10.6347397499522,-22.2657076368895));
#393=CARTESIAN_POINT('',(-25.9221762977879,10.1014736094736,-22.2156211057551));
#394=CARTESIAN_POINT('',(-26.5370884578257,9.03641450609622,-22.0928523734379));
#395=CARTESIAN_POINT('',(-26.8441182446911,8.50462331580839,-22.0201497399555));
#396=CARTESIAN_POINT('',(-27.4567077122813,7.44358723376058,-21.8534355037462));
#397=CARTESIAN_POINT('',(-27.7622673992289,6.9143423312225,-21.7594239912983));
#398=CARTESIAN_POINT('',(-28.6898814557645,5.3076676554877,-21.4430134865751));
#399=CARTESIAN_POINT('',(-29.3093003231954,4.23480270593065,-21.1890477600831));
#400=CARTESIAN_POINT('',(-30.2315881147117,2.63735339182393,-20.7566831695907));
#401=CARTESIAN_POINT('',(-30.5376130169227,2.10730271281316,-20.6041478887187));
#402=CARTESIAN_POINT('',(-31.1475461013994,1.05086762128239,-20.2836350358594));
#403=CARTESIAN_POINT('',(-31.4514548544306,0.524482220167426,-20.1156618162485));
#404=CARTESIAN_POINT('',(-31.7543802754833,-0.000199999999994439,-19.9407861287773));
#405=B_SPLINE_CURVE_WITH_KNOTS('',3,(#373,#374,#375,#376,#377,#378,#379,#380,#381,#382,#383,
#384,#385,#386,#387,#388,#389,#390,#391,#392,#393,#394,#395,#396,#397,#398,#399,#400,#401,#402,
#403,#404),.UNSPECIFIED.,.F.,.F.,(4,2,2,2,2,2,2,2,2,2,2,2,2,2,2,4),(0.,2.17937596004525,
4.35946654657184,6.54467421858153,8.72966408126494,10.8607692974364,12.9919155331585,
15.120523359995,17.2490654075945,19.1020483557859,20.9550047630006,22.8096400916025,
24.6642675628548,28.4552152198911,30.3473870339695,32.2390270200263),.UNSPECIFIED.);
#406=EDGE_CURVE('E116',#370,#281,#405,.T.);
#407=ORIENTED_EDGE('',*,*,#406,.T.);
#408=EDGE_LOOP('',(#327,#364,#372,#407));
#409=FACE_BOUND('',#408,.T.);
#410=ADVANCED_FACE('F114',(#409),#326,.T.);
#411=CARTESIAN_POINT('',(15.8771324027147,27.5,-23.52));
#412=DIRECTION('',(0.,1.,0.));
#413=DIRECTION('',(0.,0.,1.));
#414=AXIS2_PLACEMENT_3D('',#411,#412,#413);
#415=PLANE('',#414);
#416=ORIENTED_EDGE('',*,*,#371,.T.);
#417=CARTESIAN_POINT('',(-41.9529404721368,27.5,-14.207278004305));
#418=CARTESIAN_POINT('',(-41.3498619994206,27.5,-13.9160849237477));
#419=CARTESIAN_POINT('',(-40.7460496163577,27.5,-13.6264069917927));
#420=CARTESIAN_POINT('',(-39.5368030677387,27.5,-13.0504395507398));
#421=CARTESIAN_POINT('',(-38.9313688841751,27.5,-12.7641500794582));
#422=CARTESIAN_POINT('',(-37.7186338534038,27.5,-12.1952752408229));
#423=CARTESIAN_POINT('',(-37.111332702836,27.5,-11.9126905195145));
#424=CARTESIAN_POINT('',(-35.8948027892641,27.5,-11.3517074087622));
#425=CARTESIAN_POINT('',(-35.2855740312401,27.5,-11.0733090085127));
#426=CARTESIAN_POINT('',(-33.4476550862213,27.5,-10.2418974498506));
#427=CARTESIAN_POINT('',(-32.2157452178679,27.5,-9.69597054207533));
#428=CARTESIAN_POINT('',(-29.7417380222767,27.5,-8.62775844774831));
#429=CARTESIAN_POINT('',(-28.4996412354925,27.5,-8.10547201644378));
#430=CARTESIAN_POINT('',(-26.6200225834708,27.5,-7.34162955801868));
#431=CARTESIAN_POINT('',(-25.987043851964,27.5,-7.08888221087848));
#432=CARTESIAN_POINT('',(-24.7176705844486,27.5,-6.59212719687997));
#433=CARTESIAN_POINT('',(-24.0812761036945,27.5,-6.34811938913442));
#434=CARTESIAN_POINT('',(-22.8046783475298,27.5,-5.86996968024));
#435=CARTESIAN_POINT('',(-22.1644745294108,27.5,-5.63582922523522));
#436=CARTESIAN_POINT('',(-20.8800742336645,27.5,-5.17879930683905));
#437=CARTESIAN_POINT('',(-20.23587785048,27.5,-4.95590957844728));
#438=CARTESIAN_POINT('',(-18.9445901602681,27.5,-4.52336181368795));
#439=CARTESIAN_POINT('',(-18.2975081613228,27.5,-4.31367612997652));
#440=CARTESIAN_POINT('',(-16.9988609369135,27.5,-3.90872451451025));
#441=CARTESIAN_POINT('',(-16.3472956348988,27.5,-3.71345882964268));
#442=CARTESIAN_POINT('',(-14.3858917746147,27.5,-3.15218051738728));
#443=CARTESIAN_POINT('',(-13.0688434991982,27.5,-2.81051560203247));
#444=CARTESIAN_POINT('',(-11.0791469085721,27.5,-2.35941057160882));
#445=CARTESIAN_POINT('',(-10.4133851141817,27.5,-2.21924572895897));
#446=CARTESIAN_POINT('',(-9.07745639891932,27.5,-1.9616132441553));
#447=CARTESIAN_POINT('',(-8.40728957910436,27.5,-1.84414508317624));
#448=CARTESIAN_POINT('',(-7.06301937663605,27.5,-1.6339973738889));
#449=CARTESIAN_POINT('',(-6.38891574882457,27.5,-1.54131938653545));
#450=CARTESIAN_POINT('',(-5.03755485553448,27.5,-1.38261853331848));
#451=CARTESIAN_POINT('',(-4.36029758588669,27.5,-1.31659570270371));
#452=CARTESIAN_POINT('',(-3.0078260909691,27.5,-1.21297427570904));
#453=CARTESIAN_POINT('',(-2.33262527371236,27.5,-1.17520180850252));
#454=CARTESIAN_POINT('',(-0.981233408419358,27.5,-1.12827728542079));
#455=CARTESIAN_POINT('',(-0.305042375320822,27.5,-1.119124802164));
#456=CARTESIAN_POINT('',(1.04693403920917,27.5,-1.12965648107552));
#457=CARTESIAN_POINT('',(1.72271948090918,27.5,-1.14933283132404));
#458=CARTESIAN_POINT('',(3.07287323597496,27.5,-1.21703783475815));
#459=CARTESIAN_POINT('',(3.74724148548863,27.5,-1.26506773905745));
#460=CARTESIAN_POINT('',(5.38622566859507,27.5,-1.41526016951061));
#461=CARTESIAN_POINT('',(6.34953811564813,27.5,-1.53188000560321));
#462=CARTESIAN_POINT('',(8.26856130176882,27.5,-1.81645090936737));
#463=CARTESIAN_POINT('',(9.22427087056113,27.5,-1.98440972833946));
#464=CARTESIAN_POINT('',(11.1286083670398,27.5,-2.36594258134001));
#465=CARTESIAN_POINT('',(12.0772164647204,27.5,-2.57961465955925));
#466=CARTESIAN_POINT('',(13.9646711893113,27.5,-3.04594688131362));
#467=CARTESIAN_POINT('',(14.9035181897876,27.5,-3.29860552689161));
#468=CARTESIAN_POINT('',(16.7933423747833,27.5,-3.84312729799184));
#469=CARTESIAN_POINT('',(17.7440949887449,27.5,-4.13576455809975));
#470=CARTESIAN_POINT('',(19.6362862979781,27.5,-4.74984233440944));
#471=CARTESIAN_POINT('',(20.5777241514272,27.5,-5.07128542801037));
#472=CARTESIAN_POINT('',(22.4467523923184,27.5,-5.73620174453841));
#473=CARTESIAN_POINT('',(23.3743910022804,27.5,-6.07953993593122));
#474=CARTESIAN_POINT('',(24.7600183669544,27.5,-6.60924818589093));
#475=CARTESIAN_POINT('',(25.2208494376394,27.5,-6.78823807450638));
#476=CARTESIAN_POINT('',(26.1407238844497,27.5,-7.15071875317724));
#477=CARTESIAN_POINT('',(26.599767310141,27.5,-7.33420941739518));
#478=CARTESIAN_POINT('',(27.0579825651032,27.5,-7.51974796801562));
#479=B_SPLINE_CURVE_WITH_KNOTS('',3,(#417,#418,#419,#420,#421,#422,#423,#424,#425,#426,#427,
#428,#429,#430,#431,#432,#433,#434,#435,#436,#437,#438,#439,#440,#441,#442,#443,#444,#445,#446,
#447,#448,#449,#450,#451,#452,#453,#454,#455,#456,#457,#458,#459,#460,#461,#462,#463,#464,#465,
#466,#467,#468,#469,#470,#471,#472,#473,#474,#475,#476,#477,#478),.UNSPECIFIED.,.F.,.F.,(4,2,2,
2,2,2,2,2,2,2,2,2,2,2,2,2,2,2,2,2,2,2,2,2,2,2,2,2,2,2,4),(0.,2.00909855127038,4.01821950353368,
6.02768627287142,8.03714785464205,12.0793239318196,16.1212869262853,18.1659567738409,
20.2105936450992,22.2555291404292,24.3004164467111,26.3408689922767,28.3813564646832,
32.4607424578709,34.5015007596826,36.5422124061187,38.5830525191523,40.6238953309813,
42.6520717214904,44.6802178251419,46.7078144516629,48.7355005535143,51.6449146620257,
54.5547682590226,57.4709265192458,60.3869727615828,63.3707330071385,66.3547604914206,
69.3218933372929,70.8049872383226,72.2880397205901),.UNSPECIFIED.);
#480=CARTESIAN_POINT('',(15.8771324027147,27.5,-3.5791472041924));
#481=VERTEX_POINT('',#480);
#482=EDGE_CURVE('E100',#362,#481,#479,.T.);
#483=ORIENTED_EDGE('',*,*,#482,.T.);
#484=DIRECTION('',(0.,0.,1.));
#485=VECTOR('',#484,1.);
#486=CARTESIAN_POINT('',(15.8771324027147,27.5,-23.52));
#487=LINE('',#486,#485);
#488=CARTESIAN_POINT('',(15.8771324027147,27.5,-19.9408527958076));
#489=VERTEX_POINT('',#488);
#490=EDGE_CURVE('E119',#489,#481,#487,.T.);
#491=ORIENTED_EDGE('',*,*,#490,.F.);
#492=CARTESIAN_POINT('',(-41.9529404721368,27.5,-9.31272199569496));
#493=CARTESIAN_POINT('',(-41.3498619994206,27.5,-9.60391507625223));
#494=CARTESIAN_POINT('',(-40.7460496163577,27.5,-9.89359300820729));
#495=CARTESIAN_POINT('',(-39.5368030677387,27.5,-10.4695604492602));
#496=CARTESIAN_POINT('',(-38.9313688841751,27.5,-10.7558499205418));
#497=CARTESIAN_POINT('',(-37.7186338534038,27.5,-11.3247247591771));
#498=CARTESIAN_POINT('',(-37.111332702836,27.5,-11.6073094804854));
#499=CARTESIAN_POINT('',(-35.8948027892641,27.5,-12.1682925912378));
#500=CARTESIAN_POINT('',(-35.2855740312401,27.5,-12.4466909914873));
#501=CARTESIAN_POINT('',(-33.4476550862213,27.5,-13.2781025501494));
#502=CARTESIAN_POINT('',(-32.2157452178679,27.5,-13.8240294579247));
#503=CARTESIAN_POINT('',(-29.7417380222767,27.5,-14.8922415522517));
#504=CARTESIAN_POINT('',(-28.4996412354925,27.5,-15.4145279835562));
#505=CARTESIAN_POINT('',(-26.6200225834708,27.5,-16.1783704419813));
#506=CARTESIAN_POINT('',(-25.987043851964,27.5,-16.4311177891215));
#507=CARTESIAN_POINT('',(-24.7176705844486,27.5,-16.92787280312));
#508=CARTESIAN_POINT('',(-24.0812761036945,27.5,-17.1718806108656));
#509=CARTESIAN_POINT('',(-22.8046783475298,27.5,-17.65003031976));
#510=CARTESIAN_POINT('',(-22.1644745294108,27.5,-17.8841707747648));
#511=CARTESIAN_POINT('',(-20.8800742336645,27.5,-18.3412006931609));
#512=CARTESIAN_POINT('',(-20.23587785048,27.5,-18.5640904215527));
#513=CARTESIAN_POINT('',(-18.9445901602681,27.5,-18.996638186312));
#514=CARTESIAN_POINT('',(-18.2975081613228,27.5,-19.2063238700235));
#515=CARTESIAN_POINT('',(-16.9988609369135,27.5,-19.6112754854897));
#516=CARTESIAN_POINT('',(-16.3472956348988,27.5,-19.8065411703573));
#517=CARTESIAN_POINT('',(-14.3858917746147,27.5,-20.3678194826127));
#518=CARTESIAN_POINT('',(-13.0688434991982,27.5,-20.7094843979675));
#519=CARTESIAN_POINT('',(-11.079146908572,27.5,-21.1605894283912));
#520=CARTESIAN_POINT('',(-10.4133851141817,27.5,-21.300754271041));
#521=CARTESIAN_POINT('',(-9.07745639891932,27.5,-21.5583867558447));
#522=CARTESIAN_POINT('',(-8.40728957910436,27.5,-21.6758549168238));
#523=CARTESIAN_POINT('',(-7.06301937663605,27.5,-21.8860026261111));
#524=CARTESIAN_POINT('',(-6.38891574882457,27.5,-21.9786806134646));
#525=CARTESIAN_POINT('',(-5.03755485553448,27.5,-22.1373814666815));
#526=CARTESIAN_POINT('',(-4.36029758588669,27.5,-22.2034042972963));
#527=CARTESIAN_POINT('',(-3.0078260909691,27.5,-22.307025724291));
#528=CARTESIAN_POINT('',(-2.33262527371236,27.5,-22.3447981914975));
#529=CARTESIAN_POINT('',(-0.981233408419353,27.5,-22.3917227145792));
#530=CARTESIAN_POINT('',(-0.305042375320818,27.5,-22.400875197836));
#531=CARTESIAN_POINT('',(1.04693403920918,27.5,-22.3903435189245));
#532=CARTESIAN_POINT('',(1.72271948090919,27.5,-22.370667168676));
#533=CARTESIAN_POINT('',(3.07287323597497,27.5,-22.3029621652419));
#534=CARTESIAN_POINT('',(3.74724148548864,27.5,-22.2549322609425));
#535=CARTESIAN_POINT('',(5.38622566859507,27.5,-22.1047398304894));
#536=CARTESIAN_POINT('',(6.34953811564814,27.5,-21.9881199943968));
#537=CARTESIAN_POINT('',(8.26856130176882,27.5,-21.7035490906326));
#538=CARTESIAN_POINT('',(9.22427087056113,27.5,-21.5355902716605));
#539=CARTESIAN_POINT('',(11.1286083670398,27.5,-21.15405741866));
#540=CARTESIAN_POINT('',(12.0772164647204,27.5,-20.9403853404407));
#541=CARTESIAN_POINT('',(13.9646711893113,27.5,-20.4740531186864));
#542=CARTESIAN_POINT('',(14.9035181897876,27.5,-20.2213944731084));
#543=CARTESIAN_POINT('',(16.7933423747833,27.5,-19.6768727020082));
#544=CARTESIAN_POINT('',(17.7440949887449,27.5,-19.3842354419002));
#545=CARTESIAN_POINT('',(19.6362862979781,27.5,-18.7701576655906));
#546=CARTESIAN_POINT('',(20.5777241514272,27.5,-18.4487145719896));
#547=CARTESIAN_POINT('',(22.4467523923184,27.5,-17.7837982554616));
#548=CARTESIAN_POINT('',(23.3743910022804,27.5,-17.4404600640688));
#549=CARTESIAN_POINT('',(24.7600183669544,27.5,-16.9107518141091));
#550=CARTESIAN_POINT('',(25.2208494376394,27.5,-16.7317619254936));
#551=CARTESIAN_POINT('',(26.1407238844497,27.5,-16.3692812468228));
#552=CARTESIAN_POINT('',(26.599767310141,27.5,-16.1857905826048));
#553=CARTESIAN_POINT('',(27.0579825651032,27.5,-16.0002520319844));
#554=B_SPLINE_CURVE_WITH_KNOTS('',3,(#492,#493,#494,#495,#496,#497,#498,#499,#500,#501,#502,
#503,#504,#505,#506,#507,#508,#509,#510,#511,#512,#513,#514,#515,#516,#517,#518,#519,#520,#521,
#522,#523,#524,#525,#526,#527,#528,#529,#530,#531,#532,#533,#534,#535,#536,#537,#538,#539,#540,
#541,#542,#543,#544,#545,#546,#547,#548,#549,#550,#551,#552,#553),.UNSPECIFIED.,.F.,.F.,(4,2,2,
2,2,2,2,2,2,2,2,2,2,2,2,2,2,2,2,2,2,2,2,2,2,2,2,2,2,2,4),(0.,2.00909855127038,4.01821950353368,
6.02768627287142,8.03714785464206,12.0793239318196,16.1212869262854,18.165956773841,
20.2105936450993,22.2555291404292,24.3004164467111,26.3408689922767,28.3813564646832,
32.4607424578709,34.5015007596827,36.5422124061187,38.5830525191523,40.6238953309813,
42.6520717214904,44.6802178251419,46.707814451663,48.7355005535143,51.6449146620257,
54.5547682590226,57.4709265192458,60.3869727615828,63.3707330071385,66.3547604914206,
69.3218933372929,70.8049872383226,72.2880397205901),.UNSPECIFIED.);
#555=EDGE_CURVE('E231',#489,#370,#554,.F.);
#556=ORIENTED_EDGE('',*,*,#555,.T.);
#557=EDGE_LOOP('',(#416,#483,#491,#556));
#558=FACE_BOUND('',#557,.T.);
#559=ADVANCED_FACE('F222',(#558),#415,.T.);
#560=CARTESIAN_POINT('',(31.7542648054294,0.,-23.52));
#561=DIRECTION('',(0.866025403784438,0.5,0.));
#562=DIRECTION('',(-0.5,0.866025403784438,0.));
#563=AXIS2_PLACEMENT_3D('',#560,#561,#562);
#564=PLANE('',#563);
#565=ORIENTED_EDGE('',*,*,#490,.T.);
#566=CARTESIAN_POINT('',(15.8770169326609,27.5002,-3.5792138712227));
#567=CARTESIAN_POINT('',(16.2259892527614,26.8957622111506,-3.37774962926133));
#568=CARTESIAN_POINT('',(16.5763227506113,26.2889667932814,-3.18542761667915));
#569=CARTESIAN_POINT('',(17.2797989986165,25.0705101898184,-2.8216092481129));
#570=CARTESIAN_POINT('',(17.6329426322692,24.4588474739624,-2.6501197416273));
#571=CARTESIAN_POINT('',(18.3427291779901,23.229461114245,-2.33026818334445));
#572=CARTESIAN_POINT('',(18.6993783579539,22.6117266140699,-2.18196136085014));
#573=CARTESIAN_POINT('',(19.4151397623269,21.371991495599,-1.91167004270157));
#574=CARTESIAN_POINT('',(19.7742517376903,20.7499913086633,-1.78968292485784));
#575=CARTESIAN_POINT('',(20.4857595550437,19.5176236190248,-1.57720918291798));
#576=CARTESIAN_POINT('',(20.8381026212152,18.907347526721,-1.48601990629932));
#577=CARTESIAN_POINT('',(21.5444032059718,17.683999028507,-1.33311646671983));
#578=CARTESIAN_POINT('',(21.8983607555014,17.0709265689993,-1.27140287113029));
#579=CARTESIAN_POINT('',(22.6068704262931,15.8437518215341,-1.17900903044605));
#580=CARTESIAN_POINT('',(22.9614213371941,15.2296516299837,-1.14829190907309));
#581=CARTESIAN_POINT('',(23.6708503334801,14.0008845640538,-1.11855157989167));
#582=CARTESIAN_POINT('',(24.025728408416,13.3862177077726,-1.11952739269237));
#583=CARTESIAN_POINT('',(24.6891773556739,12.2370904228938,-1.15095918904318));
#584=CARTESIAN_POINT('',(24.9977954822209,11.7025481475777,-1.17758234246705));
#585=CARTESIAN_POINT('',(25.6142949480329,10.6347397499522,-1.25429236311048));
#586=CARTESIAN_POINT('',(25.9221762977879,10.1014736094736,-1.3043788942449));
#587=CARTESIAN_POINT('',(26.5370884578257,9.03641450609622,-1.42714762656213));
#588=CARTESIAN_POINT('',(26.8441182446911,8.50462331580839,-1.49985026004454));
#589=CARTESIAN_POINT('',(27.4567077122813,7.44358723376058,-1.66656449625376));
#590=CARTESIAN_POINT('',(27.7622673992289,6.9143423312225,-1.76057600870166));
#591=CARTESIAN_POINT('',(28.6898814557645,5.3076676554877,-2.07698651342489));
#592=CARTESIAN_POINT('',(29.3093003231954,4.23480270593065,-2.33095223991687));
#593=CARTESIAN_POINT('',(30.2315881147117,2.63735339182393,-2.76331683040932));
#594=CARTESIAN_POINT('',(30.5376130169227,2.10730271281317,-2.91585211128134));
#595=CARTESIAN_POINT('',(31.1475461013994,1.05086762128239,-3.23636496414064));
#596=CARTESIAN_POINT('',(31.4514548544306,0.524482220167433,-3.40433818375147));
#597=CARTESIAN_POINT('',(31.7543802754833,-0.000199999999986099,-3.5792138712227));
#598=B_SPLINE_CURVE_WITH_KNOTS('',3,(#566,#567,#568,#569,#570,#571,#572,#573,#574,#575,#576,
#577,#578,#579,#580,#581,#582,#583,#584,#585,#586,#587,#588,#589,#590,#591,#592,#593,#594,#595,
#596,#597),.UNSPECIFIED.,.F.,.F.,(4,2,2,2,2,2,2,2,2,2,2,2,2,2,2,4),(0.,2.17937596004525,
4.35946654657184,6.54467421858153,8.72966408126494,10.8607692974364,12.9919155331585,
15.120523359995,17.2490654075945,19.1020483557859,20.9550047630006,22.8096400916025,
24.6642675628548,28.4552152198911,30.3473870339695,32.2390270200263),.UNSPECIFIED.);
#599=CARTESIAN_POINT('',(31.7542648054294,0.,-3.5791472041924));
#600=VERTEX_POINT('',#599);
#601=EDGE_CURVE('E211',#481,#600,#598,.T.);
#602=ORIENTED_EDGE('',*,*,#601,.T.);
#603=DIRECTION('',(0.,0.,1.));
#604=VECTOR('',#603,1.);
#605=CARTESIAN_POINT('',(31.7542648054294,0.,-23.52));
#606=LINE('',#605,#604);
#607=CARTESIAN_POINT('',(31.7542648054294,0.,-19.9408527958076));
#608=VERTEX_POINT('',#607);
#609=EDGE_CURVE('E127',#608,#600,#606,.T.);
#610=ORIENTED_EDGE('',*,*,#609,.F.);
#611=CARTESIAN_POINT('',(31.7543802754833,-0.000199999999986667,-19.9407861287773));
#612=CARTESIAN_POINT('',(31.4054079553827,0.604237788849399,-20.1422503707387));
#613=CARTESIAN_POINT('',(31.0550744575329,1.21103320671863,-20.3345723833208));
#614=CARTESIAN_POINT('',(30.3515982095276,2.42948981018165,-20.6983907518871));
#615=CARTESIAN_POINT('',(29.9984545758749,3.04115252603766,-20.8698802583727));
#616=CARTESIAN_POINT('',(29.288668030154,4.27053888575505,-21.1897318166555));
#617=CARTESIAN_POINT('',(28.9320188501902,4.88827338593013,-21.3380386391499));
#618=CARTESIAN_POINT('',(28.2162574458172,6.12800850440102,-21.6083299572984));
#619=CARTESIAN_POINT('',(27.8571454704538,6.75000869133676,-21.7303170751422));
#620=CARTESIAN_POINT('',(27.1456376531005,7.98237638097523,-21.942790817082));
#621=CARTESIAN_POINT('',(26.7932945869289,8.59265247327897,-22.0339800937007));
#622=CARTESIAN_POINT('',(26.0869940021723,9.81600097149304,-22.1868835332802));
#623=CARTESIAN_POINT('',(25.7330364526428,10.4290734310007,-22.2485971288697));
#624=CARTESIAN_POINT('',(25.024526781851,11.6562481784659,-22.3409909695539));
#625=CARTESIAN_POINT('',(24.66997587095,12.2703483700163,-22.3717080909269));
#626=CARTESIAN_POINT('',(23.960546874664,13.4991154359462,-22.4014484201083));
#627=CARTESIAN_POINT('',(23.6056687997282,14.1137822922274,-22.4004726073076));
#628=CARTESIAN_POINT('',(22.9422198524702,15.2629095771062,-22.3690408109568));
#629=CARTESIAN_POINT('',(22.6336017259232,15.7974518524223,-22.3424176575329));
#630=CARTESIAN_POINT('',(22.0171022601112,16.8652602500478,-22.2657076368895));
#631=CARTESIAN_POINT('',(21.7092209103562,17.3985263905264,-22.2156211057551));
#632=CARTESIAN_POINT('',(21.0943087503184,18.4635854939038,-22.0928523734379));
#633=CARTESIAN_POINT('',(20.787278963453,18.9953766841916,-22.0201497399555));
#634=CARTESIAN_POINT('',(20.1746894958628,20.0564127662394,-21.8534355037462));
#635=CARTESIAN_POINT('',(19.8691298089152,20.5856576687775,-21.7594239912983));
#636=CARTESIAN_POINT('',(18.9415157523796,22.1923323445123,-21.4430134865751));
#637=CARTESIAN_POINT('',(18.3220968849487,23.2651972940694,-21.1890477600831));
#638=CARTESIAN_POINT('',(17.3998090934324,24.8626466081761,-20.7566831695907));
#639=CARTESIAN_POINT('',(17.0937841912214,25.3926972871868,-20.6041478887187));
#640=CARTESIAN_POINT('',(16.4838511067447,26.4491323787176,-20.2836350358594));
#641=CARTESIAN_POINT('',(16.1799423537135,26.9755177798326,-20.1156618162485));
#642=CARTESIAN_POINT('',(15.8770169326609,27.5002,-19.9407861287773));
#643=B_SPLINE_CURVE_WITH_KNOTS('',3,(#611,#612,#613,#614,#615,#616,#617,#618,#619,#620,#621,
#622,#623,#624,#625,#626,#627,#628,#629,#630,#631,#632,#633,#634,#635,#636,#637,#638,#639,#640,
#641,#642),.UNSPECIFIED.,.F.,.F.,(4,2,2,2,2,2,2,2,2,2,2,2,2,2,2,4),(0.,2.17937596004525,
4.35946654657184,6.54467421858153,8.72966408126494,10.8607692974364,12.9919155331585,
15.120523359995,17.2490654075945,19.1020483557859,20.9550047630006,22.8096400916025,
24.6642675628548,28.4552152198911,30.3473870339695,32.2390270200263),.UNSPECIFIED.);
#644=EDGE_CURVE('E69',#608,#489,#643,.T.);
#645=ORIENTED_EDGE('',*,*,#644,.T.);
#646=EDGE_LOOP('',(#565,#602,#610,#645));
#647=FACE_BOUND('',#646,.T.);
#648=ADVANCED_FACE('F226',(#647),#564,.T.);
#649=CARTESIAN_POINT('',(15.8771324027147,-27.5,-23.52));
#650=DIRECTION('',(0.866025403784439,-0.5,0.));
#651=DIRECTION('',(0.5,0.866025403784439,0.));
#652=AXIS2_PLACEMENT_3D('',#649,#650,#651);
#653=PLANE('',#652);
#654=ORIENTED_EDGE('',*,*,#609,.T.);
#655=CARTESIAN_POINT('',(31.7543802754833,0.000200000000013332,-3.5792138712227));
#656=CARTESIAN_POINT('',(31.4054079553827,-0.604237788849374,-3.37774962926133));
#657=CARTESIAN_POINT('',(31.0550744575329,-1.21103320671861,-3.18542761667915));
#658=CARTESIAN_POINT('',(30.3515982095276,-2.42948981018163,-2.8216092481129));
#659=CARTESIAN_POINT('',(29.9984545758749,-3.04115252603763,-2.6501197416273));
#660=CARTESIAN_POINT('',(29.288668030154,-4.27053888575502,-2.33026818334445));
#661=CARTESIAN_POINT('',(28.9320188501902,-4.8882733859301,-2.18196136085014));
#662=CARTESIAN_POINT('',(28.2162574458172,-6.128008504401,-1.91167004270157));
#663=CARTESIAN_POINT('',(27.8571454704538,-6.75000869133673,-1.78968292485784));
#664=CARTESIAN_POINT('',(27.1456376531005,-7.9823763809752,-1.57720918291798));
#665=CARTESIAN_POINT('',(26.7932945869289,-8.59265247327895,-1.48601990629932));
#666=CARTESIAN_POINT('',(26.0869940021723,-9.81600097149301,-1.33311646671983));
#667=CARTESIAN_POINT('',(25.7330364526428,-10.4290734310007,-1.27140287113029));
#668=CARTESIAN_POINT('',(25.024526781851,-11.6562481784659,-1.17900903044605));
#669=CARTESIAN_POINT('',(24.66997587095,-12.2703483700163,-1.14829190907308));
#670=CARTESIAN_POINT('',(23.960546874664,-13.4991154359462,-1.11855157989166));
#671=CARTESIAN_POINT('',(23.6056687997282,-14.1137822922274,-1.11952739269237));
#672=CARTESIAN_POINT('',(22.9422198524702,-15.2629095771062,-1.15095918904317));
#673=CARTESIAN_POINT('',(22.6336017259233,-15.7974518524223,-1.17758234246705));
#674=CARTESIAN_POINT('',(22.0171022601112,-16.8652602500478,-1.25429236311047));
#675=CARTESIAN_POINT('',(21.7092209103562,-17.3985263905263,-1.3043788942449));
#676=CARTESIAN_POINT('',(21.0943087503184,-18.4635854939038,-1.42714762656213));
#677=CARTESIAN_POINT('',(20.787278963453,-18.9953766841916,-1.49985026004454));
#678=CARTESIAN_POINT('',(20.1746894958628,-20.0564127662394,-1.66656449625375));
#679=CARTESIAN_POINT('',(19.8691298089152,-20.5856576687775,-1.76057600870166));
#680=CARTESIAN_POINT('',(18.9415157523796,-22.1923323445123,-2.07698651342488));
#681=CARTESIAN_POINT('',(18.3220968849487,-23.2651972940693,-2.33095223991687));
#682=CARTESIAN_POINT('',(17.3998090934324,-24.8626466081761,-2.76331683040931));
#683=CARTESIAN_POINT('',(17.0937841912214,-25.3926972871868,-2.91585211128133));
#684=CARTESIAN_POINT('',(16.4838511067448,-26.4491323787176,-3.23636496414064));
#685=CARTESIAN_POINT('',(16.1799423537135,-26.9755177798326,-3.40433818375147));
#686=CARTESIAN_POINT('',(15.8770169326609,-27.5002,-3.5792138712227));
#687=B_SPLINE_CURVE_WITH_KNOTS('',3,(#655,#656,#657,#658,#659,#660,#661,#662,#663,#664,#665,
#666,#667,#668,#669,#670,#671,#672,#673,#674,#675,#676,#677,#678,#679,#680,#681,#682,#683,#684,
#685,#686),.UNSPECIFIED.,.F.,.F.,(4,2,2,2,2,2,2,2,2,2,2,2,2,2,2,4),(0.,2.17937596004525,
4.35946654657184,6.54467421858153,8.72966408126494,10.8607692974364,12.9919155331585,
15.120523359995,17.2490654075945,19.1020483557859,20.9550047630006,22.8096400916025,
24.6642675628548,28.4552152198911,30.3473870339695,32.2390270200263),.UNSPECIFIED.);
#688=EDGE_CURVE('E203',#600,#87,#687,.T.);
#689=ORIENTED_EDGE('',*,*,#688,.T.);
#690=ORIENTED_EDGE('',*,*,#88,.F.);
#691=CARTESIAN_POINT('',(15.8770169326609,-27.5002,-19.9407861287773));
#692=CARTESIAN_POINT('',(16.2259892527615,-26.8957622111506,-20.1422503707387));
#693=CARTESIAN_POINT('',(16.5763227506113,-26.2889667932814,-20.3345723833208));
#694=CARTESIAN_POINT('',(17.2797989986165,-25.0705101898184,-20.6983907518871));
#695=CARTESIAN_POINT('',(17.6329426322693,-24.4588474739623,-20.8698802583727));
#696=CARTESIAN_POINT('',(18.3427291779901,-23.229461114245,-21.1897318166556));
#697=CARTESIAN_POINT('',(18.6993783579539,-22.6117266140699,-21.3380386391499));
#698=CARTESIAN_POINT('',(19.4151397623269,-21.371991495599,-21.6083299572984));
#699=CARTESIAN_POINT('',(19.7742517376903,-20.7499913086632,-21.7303170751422));
#700=CARTESIAN_POINT('',(20.4857595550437,-19.5176236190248,-21.942790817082));
#701=CARTESIAN_POINT('',(20.8381026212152,-18.907347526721,-22.0339800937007));
#702=CARTESIAN_POINT('',(21.5444032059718,-17.683999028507,-22.1868835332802));
#703=CARTESIAN_POINT('',(21.8983607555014,-17.0709265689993,-22.2485971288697));
#704=CARTESIAN_POINT('',(22.6068704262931,-15.8437518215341,-22.3409909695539));
#705=CARTESIAN_POINT('',(22.9614213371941,-15.2296516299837,-22.3717080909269));
#706=CARTESIAN_POINT('',(23.6708503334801,-14.0008845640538,-22.4014484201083));
#707=CARTESIAN_POINT('',(24.025728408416,-13.3862177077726,-22.4004726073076));
#708=CARTESIAN_POINT('',(24.6891773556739,-12.2370904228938,-22.3690408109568));
#709=CARTESIAN_POINT('',(24.9977954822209,-11.7025481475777,-22.3424176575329));
#710=CARTESIAN_POINT('',(25.6142949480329,-10.6347397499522,-22.2657076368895));
#711=CARTESIAN_POINT('',(25.9221762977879,-10.1014736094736,-22.2156211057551));
#712=CARTESIAN_POINT('',(26.5370884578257,-9.0364145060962,-22.0928523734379));
#713=CARTESIAN_POINT('',(26.8441182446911,-8.50462331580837,-22.0201497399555));
#714=CARTESIAN_POINT('',(27.4567077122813,-7.44358723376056,-21.8534355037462));
#715=CARTESIAN_POINT('',(27.7622673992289,-6.91434233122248,-21.7594239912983));
#716=CARTESIAN_POINT('',(28.6898814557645,-5.30766765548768,-21.4430134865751));
#717=CARTESIAN_POINT('',(29.3093003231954,-4.23480270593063,-21.1890477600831));
#718=CARTESIAN_POINT('',(30.2315881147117,-2.63735339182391,-20.7566831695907));
#719=CARTESIAN_POINT('',(30.5376130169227,-2.10730271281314,-20.6041478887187));
#720=CARTESIAN_POINT('',(31.1475461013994,-1.05086762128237,-20.2836350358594));
#721=CARTESIAN_POINT('',(31.4514548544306,-0.524482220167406,-20.1156618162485));
#722=CARTESIAN_POINT('',(31.7543802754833,0.000200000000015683,-19.9407861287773));
#723=B_SPLINE_CURVE_WITH_KNOTS('',3,(#691,#692,#693,#694,#695,#696,#697,#698,#699,#700,#701,
#702,#703,#704,#705,#706,#707,#708,#709,#710,#711,#712,#713,#714,#715,#716,#717,#718,#719,#720,
#721,#722),.UNSPECIFIED.,.F.,.F.,(4,2,2,2,2,2,2,2,2,2,2,2,2,2,2,4),(0.,2.17937596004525,
4.35946654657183,6.54467421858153,8.72966408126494,10.8607692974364,12.9919155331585,
15.120523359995,17.2490654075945,19.1020483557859,20.9550047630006,22.8096400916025,
24.6642675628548,28.4552152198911,30.3473870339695,32.2390270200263),.UNSPECIFIED.);
#724=EDGE_CURVE('E263',#85,#608,#723,.T.);
#725=ORIENTED_EDGE('',*,*,#724,.T.);
#726=EDGE_LOOP('',(#654,#689,#690,#725));
#727=FACE_BOUND('',#726,.T.);
#728=ADVANCED_FACE('F260',(#727),#653,.T.);
#729=CARTESIAN_POINT('',(0.,0.,-23.52));
#730=DIRECTION('',(0.,0.,1.));
#731=DIRECTION('',(1.,0.,0.));
#732=AXIS2_PLACEMENT_3D('',#729,#730,#731);
#733=CONICAL_SURFACE('',#732,25.555,1.0471975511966);
#734=ORIENTED_EDGE('',*,*,#317,.F.);
#735=ORIENTED_EDGE('',*,*,#406,.F.);
#736=ORIENTED_EDGE('',*,*,#555,.F.);
#737=ORIENTED_EDGE('',*,*,#644,.F.);
#738=ORIENTED_EDGE('',*,*,#724,.F.);
#739=ORIENTED_EDGE('',*,*,#228,.F.);
#740=EDGE_LOOP('',(#734,#735,#736,#737,#738,#739));
#741=FACE_BOUND('',#740,.T.);
#742=ORIENTED_EDGE('',*,*,#31,.F.);
#743=EDGE_LOOP('',(#742));
#744=FACE_BOUND('',#743,.T.);
#745=ADVANCED_FACE('F196',(#741,#744),#733,.T.);
#746=CARTESIAN_POINT('',(0.,0.,-3.5791472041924));
#747=DIRECTION('',(0.,0.,-1.));
#748=DIRECTION('',(-1.,0.,0.));
#749=AXIS2_PLACEMENT_3D('',#746,#747,#748);
#750=CONICAL_SURFACE('',#749,31.7542648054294,1.0471975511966);
#751=CARTESIAN_POINT('',(0.,0.,5.6843418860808E-11));
#752=DIRECTION('',(0.,0.,1.));
#753=DIRECTION('',(1.,0.,0.));
#754=AXIS2_PLACEMENT_3D('',#751,#752,#753);
#755=CIRCLE('',#754,25.5549999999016);
#756=CARTESIAN_POINT('',(25.5549999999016,0.,5.6843418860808E-11));
#757=VERTEX_POINT('',#756);
#758=EDGE_CURVE('E271',#757,#757,#755,.F.);
#759=ORIENTED_EDGE('',*,*,#758,.T.);
#760=EDGE_LOOP('',(#759));
#761=FACE_BOUND('',#760,.T.);
#762=ORIENTED_EDGE('',*,*,#688,.F.);
#763=ORIENTED_EDGE('',*,*,#601,.F.);
#764=ORIENTED_EDGE('',*,*,#482,.F.);
#765=ORIENTED_EDGE('',*,*,#363,.F.);
#766=ORIENTED_EDGE('',*,*,#274,.F.);
#767=ORIENTED_EDGE('',*,*,#155,.F.);
#768=EDGE_LOOP('',(#762,#763,#764,#765,#766,#767));
#769=FACE_BOUND('',#768,.T.);
#770=ADVANCED_FACE('F98',(#761,#769),#750,.T.);
#771=CARTESIAN_POINT('',(0.,0.,130.364689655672));
#772=DIRECTION('',(0.,0.,-1.));
#773=DIRECTION('',(-1.,0.,0.));
#774=AXIS2_PLACEMENT_3D('',#771,#772,#773);
#775=CYLINDRICAL_SURFACE('',#774,26.9);
#776=CARTESIAN_POINT('',(0.,0.,14.304));
#777=DIRECTION('',(0.,0.,1.));
#778=DIRECTION('',(1.,0.,0.));
#779=AXIS2_PLACEMENT_3D('',#776,#777,#778);
#780=CIRCLE('',#779,26.9);
#781=CARTESIAN_POINT('',(26.9,0.,14.304));
#782=VERTEX_POINT('',#781);
#783=EDGE_CURVE('E12',#782,#782,#780,.F.);
#784=ORIENTED_EDGE('',*,*,#783,.T.);
#785=EDGE_LOOP('',(#784));
#786=FACE_BOUND('',#785,.T.);
#787=CARTESIAN_POINT('',(0.,0.,5.6843418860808E-11));
#788=DIRECTION('',(0.,0.,1.));
#789=DIRECTION('',(1.,0.,0.));
#790=AXIS2_PLACEMENT_3D('',#787,#788,#789);
#791=CIRCLE('',#790,26.9);
#792=CARTESIAN_POINT('',(26.9,0.,5.6843418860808E-11));
#793=VERTEX_POINT('',#792);
#794=EDGE_CURVE('E273',#793,#793,#791,.T.);
#795=ORIENTED_EDGE('',*,*,#794,.T.);
#796=EDGE_LOOP('',(#795));
#797=FACE_BOUND('',#796,.T.);
#798=ADVANCED_FACE('F199',(#786,#797),#775,.T.);
#799=CARTESIAN_POINT('',(0.,0.,5.6843418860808E-11));
#800=DIRECTION('',(0.,0.,1.));
#801=DIRECTION('',(1.,0.,0.));
#802=AXIS2_PLACEMENT_3D('',#799,#800,#801);
#803=PLANE('',#802);
#804=ORIENTED_EDGE('',*,*,#758,.F.);
#805=EDGE_LOOP('',(#804));
#806=FACE_BOUND('',#805,.T.);
#807=ORIENTED_EDGE('',*,*,#794,.F.);
#808=EDGE_LOOP('',(#807));
#809=FACE_BOUND('',#808,.T.);
#810=ADVANCED_FACE('F291',(#806,#809),#803,.F.);
#811=CARTESIAN_POINT('',(15.8771324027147,-27.5,15.38));
#812=DIRECTION('',(0.,0.,1.));
#813=DIRECTION('',(1.,0.,0.));
#814=AXIS2_PLACEMENT_3D('',#811,#812,#813);
#815=PLANE('',#814);
#816=CARTESIAN_POINT('',(0.,0.,15.38));
#817=DIRECTION('',(0.,0.,1.));
#818=DIRECTION('',(1.,0.,0.));
#819=AXIS2_PLACEMENT_3D('',#816,#817,#818);
#820=CIRCLE('',#819,25.824);
#821=CARTESIAN_POINT('',(25.824,0.,15.38));
#822=VERTEX_POINT('',#821);
#823=EDGE_CURVE('E51',#822,#822,#820,.T.);
#824=ORIENTED_EDGE('',*,*,#823,.T.);
#825=EDGE_LOOP('',(#824));
#826=FACE_BOUND('',#825,.T.);
#827=ORIENTED_EDGE('',*,*,#59,.F.);
#828=EDGE_LOOP('',(#827));
#829=FACE_BOUND('',#828,.T.);
#830=ADVANCED_FACE('F132',(#826,#829),#815,.T.);
#831=CARTESIAN_POINT('',(0.,0.,-21.57));
#832=DIRECTION('',(0.,0.,-1.));
#833=DIRECTION('',(-1.,0.,0.));
#834=AXIS2_PLACEMENT_3D('',#831,#832,#833);
#835=CONICAL_SURFACE('',#834,17.5,0.785398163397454);
#836=ORIENTED_EDGE('',*,*,#42,.T.);
#837=EDGE_LOOP('',(#836));
#838=FACE_BOUND('',#837,.T.);
#839=ORIENTED_EDGE('',*,*,#70,.F.);
#840=EDGE_LOOP('',(#839));
#841=FACE_BOUND('',#840,.T.);
#842=ADVANCED_FACE('F138',(#838,#841),#835,.F.);
#843=CARTESIAN_POINT('',(0.,0.,15.38));
#844=DIRECTION('',(0.,0.,-1.));
#845=DIRECTION('',(-1.,0.,0.));
#846=AXIS2_PLACEMENT_3D('',#843,#844,#845);
#847=CONICAL_SURFACE('',#846,25.824,0.785398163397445);
#848=ORIENTED_EDGE('',*,*,#783,.F.);
#849=EDGE_LOOP('',(#848));
#850=FACE_BOUND('',#849,.T.);
#851=ORIENTED_EDGE('',*,*,#823,.F.);
#852=EDGE_LOOP('',(#851));
#853=FACE_BOUND('',#852,.T.);
#854=ADVANCED_FACE('F44',(#850,#853),#847,.T.);
#855=CLOSED_SHELL('',(#46,#74,#232,#321,#410,#559,#648,#728,#745,#770,#798,#810,#830,#842,#854));
#856=MANIFOLD_SOLID_BREP('B2',#855);
#857=ADVANCED_BREP_SHAPE_REPRESENTATION('',(#18,#856),#14);
#858=SHAPE_DEFINITION_REPRESENTATION(#9,#857);
ENDSEC;
END-ISO-10303-21;
